VERSION 5.8 ;
BUSBITCHARS "[]" ;
DIVIDERCHAR "/" ;
CLEARANCEMEASURE EUCLIDEAN ;

SITE coresite
    SIZE 0.0450 BY 0.1440 ;
    CLASS CORE ;
    SYMMETRY Y ;
END coresite

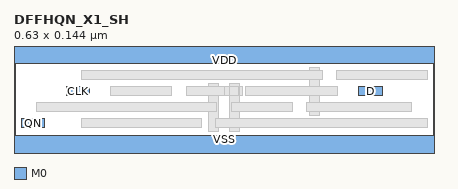
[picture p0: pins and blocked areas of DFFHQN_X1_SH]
MACRO DFFHQN_X1_SH
  CLASS CORE ;
  ORIGIN 0 0 ;
  FOREIGN DFFHQN_X1_SH 0 0 ;
  SIZE 0.6300 BY 0.1440 ;
  SYMMETRY X Y ;
  SITE coresite ;
  PIN QN
    DIRECTION OUTPUT ;
    USE SIGNAL ;
    PORT
      LAYER M0 ;
        RECT 0.0105 0.0430 0.0450 0.0290 ;
    END
  END QN
  PIN CLK
    DIRECTION INPUT ;
    USE SIGNAL ;
    PORT
      LAYER M0 ;
        RECT 0.0780 0.0910 0.1125 0.0770 ;
    END
  END CLK
  PIN D
    DIRECTION INPUT ;
    USE SIGNAL ;
    PORT
      LAYER M0 ;
        RECT 0.5175 0.0910 0.5520 0.0770 ;
    END
  END D
  PIN VSS
    DIRECTION INOUT ;
    USE GROUND ;
    SHAPE ABUTMENT ;
    PORT
      LAYER M0 ;
        RECT 0.0000 -0.0180 0.6300 0.0180 ;
    END
  END VSS
  PIN VDD
    DIRECTION INOUT ;
    USE POWER ;
    SHAPE ABUTMENT ;
    PORT
      LAYER M0 ;
        RECT 0.0000 0.1260 0.6300 0.1620 ;
    END
  END VDD
  OBS
      LAYER M2 ;
        RECT 0.2880 0.0770 0.3420 0.0910 ;
      LAYER V0 ;
        RECT 0.4430 0.1010 0.4570 0.1150 ;
        RECT 0.4430 0.0530 0.4570 0.0670 ;
        RECT 0.2930 0.0770 0.3070 0.0910 ;
        RECT 0.3230 0.0290 0.3370 0.0430 ;
      LAYER M1 ;
        RECT 0.2925 0.0960 0.3075 0.0240 ;
        RECT 0.3225 0.0960 0.3375 0.0240 ;
        RECT 0.4425 0.1200 0.4575 0.0480 ;
      LAYER V1 ;
        RECT 0.2930 0.0770 0.3070 0.0910 ;
        RECT 0.3230 0.0770 0.3370 0.0910 ;
      LAYER M0 ;
        RECT 0.1005 0.0290 0.2820 0.0430 ;
        RECT 0.3030 0.0290 0.6195 0.0430 ;
        RECT 0.0330 0.0530 0.3045 0.0670 ;
        RECT 0.3255 0.0530 0.4170 0.0670 ;
        RECT 0.4380 0.0530 0.5970 0.0670 ;
        RECT 0.1455 0.0770 0.2370 0.0910 ;
        RECT 0.2580 0.0770 0.3150 0.0910 ;
        RECT 0.3480 0.0770 0.4845 0.0910 ;
        RECT 0.1005 0.1010 0.4620 0.1150 ;
        RECT 0.4830 0.1010 0.6195 0.1150 ;
  END
END DFFHQN_X1_SH

END LIBRARY
